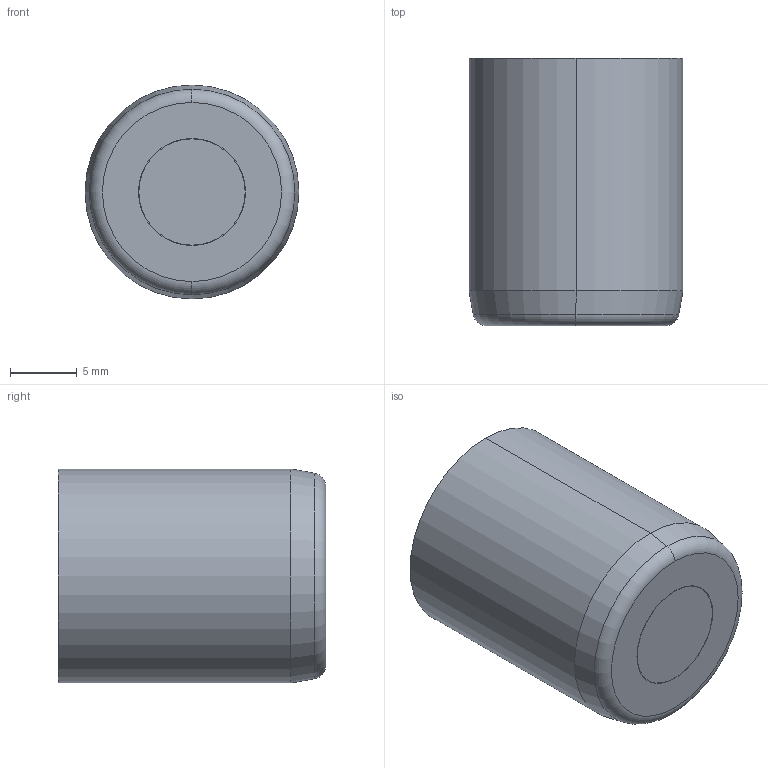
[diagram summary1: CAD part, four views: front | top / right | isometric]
STEP (ISO 10303-21) file: header records copied from the file, then geometry measured from it (millimetres).
FILE_DESCRIPTION (( 'STEP AP214' ), '1' );
FILE_NAME ('FA168700.STEP', '2013-06-28T08:06:22', ( '' ), ( '' ), 'SwSTEP 2.0', 'SolidWorks 2011', '' );
FILE_SCHEMA (( 'AUTOMOTIVE_DESIGN' ));
Length unit declared in the file: millimetre
Products named in the file (6): FA 168700-1; 9FA 168700; FA168700; FA 168700-2 comprimido; FA 168700-3; IA 8717SF
Assembly tree (5 placements, depth 2):
  FA168700
    FA 168700-2 comprimido
    FA 168700-1
    FA 168700-3
    IA 8717SF
    9FA 168700
Bounding box: 16 x 20 x 16 mm (x, y, z)
Volume: 3768.3 mm3; surface area: 2685.1 mm2
Topology: 5 solids, 5 shells, 114 faces, 259 edges, 159 vertices
Faces by surface type: plane 37, cone 34, cylinder 31, torus 10, bspline 2
Entity records: 4733 total; most frequent: CARTESIAN_POINT 1864, DIRECTION 581, ORIENTED_EDGE 514, EDGE_CURVE 257, AXIS2_PLACEMENT_3D 236, VERTEX_POINT 159, EDGE_LOOP 128, CIRCLE 116
One B-rep face of a CAD part: STEP entity #3348.
In plain terms, the cylindrical face has radius 8 mm (diameter 16 mm), a partial arc.
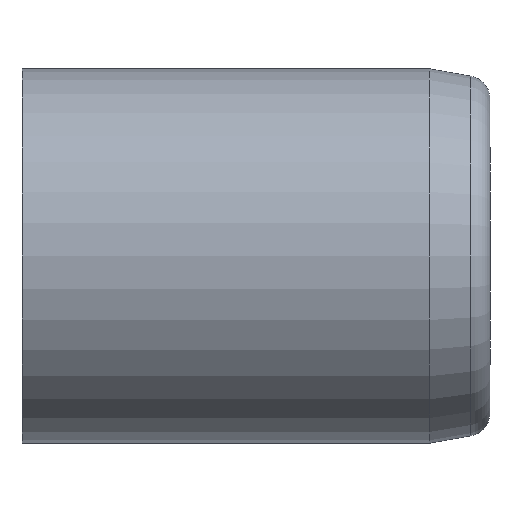
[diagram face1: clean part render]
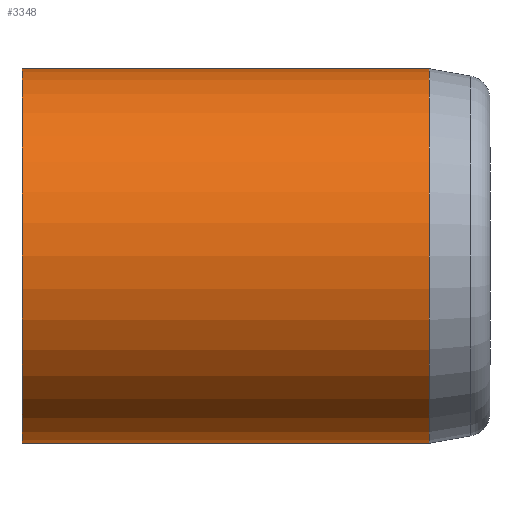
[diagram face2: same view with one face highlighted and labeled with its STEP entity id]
Its self-contained STEP definition (entity closure, numbers rounded to 3 decimals):
#39 = ORIENTED_EDGE ( 'NONE', *, *, #3433, .T. ) ;
#74 = ORIENTED_EDGE ( 'NONE', *, *, #1428, .F. ) ;
#79 = ORIENTED_EDGE ( 'NONE', *, *, #1391, .F. ) ;
#114 = ORIENTED_EDGE ( 'NONE', *, *, #1441, .F. ) ;
#273 = VERTEX_POINT ( 'NONE', #640 ) ;
#304 = VERTEX_POINT ( 'NONE', #704 ) ;
#320 = VERTEX_POINT ( 'NONE', #765 ) ;
#321 = VERTEX_POINT ( 'NONE', #758 ) ;
#640 = CARTESIAN_POINT ( 'NONE',  ( 0., 2.73, -8. ) ) ;
#704 = CARTESIAN_POINT ( 'NONE',  ( 0., 20.13, -8. ) ) ;
#758 = CARTESIAN_POINT ( 'NONE',  ( 0., 20.13, 8. ) ) ;
#765 = CARTESIAN_POINT ( 'NONE',  ( 0., 2.73, 8. ) ) ;
#976 = EDGE_LOOP ( 'NONE', ( #74, #79, #39, #114 ) ) ;
#1271 = CIRCLE ( 'NONE', #1283, 8. ) ;
#1283 = AXIS2_PLACEMENT_3D ( 'NONE', #3785, #3818, #3819 ) ;
#1391 = EDGE_CURVE ( 'NONE', #320, #273, #1271, .T. ) ;
#1428 = EDGE_CURVE ( 'NONE', #273, #304, #3889, .T. ) ;
#1441 = EDGE_CURVE ( 'NONE', #304, #321, #2631, .T. ) ;
#1631 = CYLINDRICAL_SURFACE ( 'NONE', #2755, 8. ) ;
#1632 = CARTESIAN_POINT ( 'NONE',  ( 0., -9.87, 0. ) ) ;
#1634 = DIRECTION ( 'NONE',  ( 0., 0., 1. ) ) ;
#1654 = FACE_OUTER_BOUND ( 'NONE', #976, .T. ) ;
#1655 = DIRECTION ( 'NONE',  ( 0., 1., 0. ) ) ;
#1755 = LINE ( 'NONE', #1795, #4736 ) ;
#1795 = CARTESIAN_POINT ( 'NONE',  ( 0., -9.87, 8. ) ) ;
#2233 = DIRECTION ( 'NONE',  ( 0., 1., 0. ) ) ;
#2631 = CIRCLE ( 'NONE', #2632, 8. ) ;
#2632 = AXIS2_PLACEMENT_3D ( 'NONE', #3928, #3930, #3932 ) ;
#2640 = VECTOR ( 'NONE', #3868, 1000. ) ;
#2755 = AXIS2_PLACEMENT_3D ( 'NONE', #1632, #1655, #1634 ) ;
#3348 = ADVANCED_FACE ( 'NONE', ( #1654 ), #1631, .T. ) ;
#3433 = EDGE_CURVE ( 'NONE', #320, #321, #1755, .T. ) ;
#3785 = CARTESIAN_POINT ( 'NONE',  ( 0., 2.73, 0. ) ) ;
#3818 = DIRECTION ( 'NONE',  ( 0., -1., 0. ) ) ;
#3819 = DIRECTION ( 'NONE',  ( 0., 0., -1. ) ) ;
#3868 = DIRECTION ( 'NONE',  ( 0., 1., 0. ) ) ;
#3889 = LINE ( 'NONE', #3890, #2640 ) ;
#3890 = CARTESIAN_POINT ( 'NONE',  ( 0., -9.87, -8. ) ) ;
#3928 = CARTESIAN_POINT ( 'NONE',  ( 0., 20.13, 0. ) ) ;
#3930 = DIRECTION ( 'NONE',  ( 0., 1., 0. ) ) ;
#3932 = DIRECTION ( 'NONE',  ( 0., 0., 1. ) ) ;
#4736 = VECTOR ( 'NONE', #2233, 1000. ) ;
